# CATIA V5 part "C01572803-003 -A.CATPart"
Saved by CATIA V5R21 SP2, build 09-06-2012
Part number: C01572803-003
Revision: ---
Description: PROPRIETARY NOTICE (do not delete / modify)  ***************************************************************************************************  LA SOCIETE EN COMMANDITE  AIRBUS CANADA  ("AIRBUS CANADA")  PAR  L'INTERMEDIAIRE  DE  SES  DIVISIONS  ET/OU  FILIALES  CORPORATIVES,  FOURNIT  LES PRESENTES  INFORMATIONS  AU  GOUVERNEMENT  A  TITRE CONFIDENTIEL. CES  INFORMATIONS ONT UNE TENEUR CONFIDENTIELLE,  AVEC DROITS DE PROPRIETE,  ET NOUS LES CONSIDERONS  EXCLUS  DE   L'APPLICATION  DE  LA LOI SUR L'ACCES A L'INFORMATION  (CANADA),  LES  LOIS  SUR  L'ACCES  A  L'INFORMATION  EUROPEENNES,  LE FREEDOM OF INFORMATION ACT (ETATS-UNIS) ET D'AUTRES LOIS SEMBLABLES. ELLES  PEUVENT  AUSSI  CONSTITUER DES SECRETS INDUSTRIELS DE NOTRE SOCIETE OU DE TIERCES PARTIES. LA DIVULGATION  PUBLIQUE  DE CES  INFORMATIONS NUIRAIT A AIRBUS CANADA OU A DES TIERCES PARTIES.  CES INFORMATIONS PEUVENT EGALEMENT CONTENIR  DES DONNEES QUI SONT CONTROLEE PAR DES LOIS DE CONTROLE DES EXPORTATIONS DU CANADA, L’EUROPE OU LES  ETATS-  UNIS. TOUTE EXPORTATION OU REEXPORTATION DE DONNEES CONTROLEES SANS AUTORISATION EST STRICTEMENT INTERDITE.  TOUTE INTENTION DE LES DIVULGUER EN TOUT OU EN PARTIE DEVRA ETRE SIGNIFIEE A L'AVANCE ET PAR ECRIT AU VICE-  PRESIDENT, SERVICES JURIDIQUES ET CONFORMITE ET SECRETAIRE CORPORATIF D'AIRBUS CANADA.    AIRBUS CANADA LIMITED PARTNERSHIP  ("AIRBUS CANADA"),  BY ITS AFFILIATES AND/OR SUBSIDIARIES, PROVIDES THIS  INFORMATION TO THE GOVERNMENT IN CONFIDENCE. THIS IS PROPRIETARY CONFIDENTIAL INFORMATION WHICH WE CONSIDER  EXCLUDED  FROM  THE  APPLICATION OF THE ACCESS TO INFORMATION ACT (CANADA),  THE FREEDOM OF INFORMATION ACT  (U.S.A.),  THE ACCESS TO INFORMATION LAWS IN EUROPE, AND OTHER SIMILAR LEGISLATION. AND MAY ALSO CONSTITUTE  TRADE SECRETS OF OUR  COMPANY OR THIRD PARTIES.  PUBLIC  RELEASE  OF  THIS INFORMATION  WOULD BE HARMFUL TO  AIRBUS CANADA OR THIRD PARTIES.  THIS  INFORMATION  MAY  ALSO  CONTAIN DATA THAT IS CONTROLLED BY CANADIAN,  EUROPEAN, OR U.S.A. EXPORT CONTROL LAWS. ANY UNAUTHORIZED EXPORT OR RE-EXPORT OF ANY EXPORT CONTROLLED DATA  IS STRICTLY PROHIBITED  ANY INTENTION TO DISCLOSE SUCH INFORMATION,  OR  PART THEREOF,  MUST BE NOTIFIED IN  ADVANCE AND IN WRITING TO THE VICE PRESIDENT, LEGAL AND COMPLIANCE AND CORPORATE SECRETARY OF AIRBUS CANADA.        LES RENSEIGNEMENTS,  LES DONNEES  ET  DESSINS  TECHNIQUES  DIVULGUES  DANS  LES PRESENTES SONT LA PROPRIETE  EXCLUSIVE DE LA SOCIETE EN COMMANDITE AIRBUS CANADA ("AIRBUS CANADA") OU COMPORTENT DES DROITS DE PROPRIETE  APPARTENANT  A  AUTRUI ET NE PEUVENT ETRE DIVULGUES  A  QUICONQUE  NI  UTILISES PAR QUI QUE CE SOIT SANS LE  CONSENTEMENT  ECRIT  D’AIRBUS  CANADA.  LE DETENTEUR DES  PRESENTES  S'ENGAGE, DANS TOUTES CIRCONSTANCES, A  GARDER CONFIDENTIELS LES DONNEES ET DESSINS TECHNIQUES QU'ELLES CONTIENNENT.   CE QUI PRECEDE NE S'APPLIQUE  PAS  AUX PERSONNES  QUI  ONT DES DROITS DE PROPRIETE SUR CES RENSEIGNEMENTS,  DONNEES TECHNIQUES ET DESSINS  DANS LA MESURE OU CES DROITS EXISTENT.    THE INFORMATION,  TECHNICAL DATA  AND  DESIGNS DISCLOSED HEREIN ARE THE EXCLUSIVE PROPERTY OF AIRBUS CANADA  LIMITED PARTNERSHIP  ("AIRBUS CANADA")  OR  CONTAIN PROPRIETARY RIGHTS OF OTHERS  AND ARE NOT TO BE USED OR  DISCLOSED  TO  OTHERS WITHOUT THE WRITTEN CONSENT OF AIRBUS CANADA.  THE RECIPIENT OF THIS DOCUMENT, BY ITS  RETENTION  AND  USE  AGREES TO  HOLD  IN  CONFIDENCE  THE  TECHNICAL DATA AND DESIGNS CONTAINED HEREIN. THE  FOREGOING SHALL NOT APPLY TO PERSONS HAVING PROPRIETARY RIGHTS TO SUCH INFORMATION,  TECHNICAL DATA OR SUCH  DESIGNS TO THE EXTENT THAT SUCH RIGHTS EXIST.    Copyright 2020 Airbus Canada Limited Partnership. All Rights Reserved.  ***********************************
Property "Title": "SPACER, ROLLER SHAFT, SLIDE, OWE"
Property "Dataset Type": "DETAIL"
Property "Supplier Name And CAGE Code": "AIRBUS CANADA LIMITED PARTNERSHIP L0J48"
Property "Major Supplier Code": "LP"
Property "3D Only": "Y"
Property "Material Form": "BAR - ROUND"
Property "Finish Code": "S010"
Property "PCCN": "2"
Property "Organization": "DESIGN"
Property "Dimensions": "DIMENSIONS ARE IN INCHES"
Property "Roughness": "ALL MACHINED SURFACES 125 Ra MAX"
Property "Eng. Tolerances": "LINEAR .XX= +/-.03; .XXX= +/-.010; ANGULAR= +/-0.5 DEG"
Property "Tool Design Tolerances": "LINEAR .X= +/-.06; .XX= +/-.015; .XXX= +/-.005; .XXXX= +/-.001; ANGULAR= +/-0.5 DEG"
Property "Design Authority Program": "BD-500"
Property "Color Coded": "N"
Property "Thickness": 0
Property "Inside Diameter": 0
Property "Outside Diameter": 0.75
Property "Length": 0
Property "Width": 0
Property "Wall": 0
Property "Wire Gauge": "-"
Property "Alloy": "15-5PH"
Property "Final Condition": "H1025"
Property "Density": "N/A"
Property "Form": "N/A"
Property "Grade/Composition": "N/A"
Property "Material Class": "N/A"
Property "Mesh Cell Size": "-"
Property "Standard Spec Die": "-"
Property "Type": "N/A"
Property "Style": "N/A"
Property "MFG Process": "MACHINED"
Property "Material Specification Production": "AMS5659"
Property "Material Description Production": "CRES"
Property "Project": "BA"
Publications: "PartBody", "EXTRACT_DATUM_A", "EXTRACT_DATUM_B"
Material "ST-15-5PH-B": density 7833.41 kg/m3, Young's modulus 1.9719e+11 Pa, Poisson ratio 0.27
Bounding box of the stored display mesh (mm): x -6.342 to 6.342, y -11.43 to 4.572, z -6.342 to 6.342
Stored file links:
  C:\Users\CQQZ006\Desktop\A220钢钛件\舱门\C01572803-003\C01572803-003 -A.CATPart

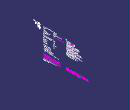
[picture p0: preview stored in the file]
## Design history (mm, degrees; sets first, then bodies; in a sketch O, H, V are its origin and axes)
AxisSystem1 "Absolute Axis System": origin (0, 0, 0), X (1, 0, 0), Y (0, 1, 0), Z (0, 0, 1)
Part_3D_Annotations1 "CATTPSSet"
Set1 "Geometrical Set for 3D Annotations"
  Set2 "No Show Geometry"
    Extract1 "EXTRACT_DATUM_A": ExtractElem face of Shaft1 from Sketch1.L2
    Extract2 "EXTRACT_DATUM_B": ExtractElem face of Shaft1 from Sketch1.L6
Body1 (main body)
  Sketch1 on yz-plane, origin (0, 0, 0), H (0, 1, 0), V (0, 0, 1)
    axis line L1 (-19.6215, 0) -> (29.3045, 0)
    point P1 (-19.6215, 0)
    line L2 (4.572, 2.0834) -> (-11.43, 2.0834)
    line L3 (-11.43, 2.0834) -> (-11.43, 3.1509)
    line L4 (-1.524, 3.5319) -> (-1.524, 6.35)
    line L5 (-1.524, 6.35) -> (0, 6.35)
    line L6 (0, 6.35) -> (0, 3.5471)
    line L7 (0.381, 3.1661) -> (4.064, 3.1661)
    line L8 (4.572, 2.8728) -> (4.572, 2.0834)
    line L9 (4.064, 3.1661) -> (4.572, 2.8728)
    point P4 (4.064, 3.1661)
    arc A1 centre (-1.905, 3.5319) radius 0.381 from (-1.524, 3.5319) to (-1.905, 3.1509) cw
    arc A2 centre (0.381, 3.5471) radius 0.381 from (0, 3.5471) to (0.381, 3.1661) ccw
    construction line L10 (-1.016, 6.35) -> (-1.524, 5.842)
    point P11 (-1.016, 6.35)
    line L11 (-11.43, 3.1509) -> (-1.905, 3.1509)
    point P16 (-1.524, 5.842)
    point P17 (-1.016, 6.35)
    distance L4 L6 = 1.524
    distance L8 L6 = 4.572
    distance L2 L1 = 2.0834
    distance L7 L1 = 3.1661
    distance L5 L1 = 6.35
    angle L7 L9 = 30
    distance P4 L8 = 0.508
    radius A1 = 0.381
    radius A2 = 0.381
    angle L5 L10 = 45
    distance L4 P11 = 0.508
    distance L6 L3 = 11.43
    distance L11 L1 = 3.1509
    coincidence: P1 H, L6 V, P11 L5, P11 L10, P16 L4, P17 L5
    horizontal: L1 H, L2 H, L5 H, L7 H, L11 H
    vertical: L3 V, L4 V, L6 V, L8 V
    tangency: A1 L4, A2 L6, A2 L7, A1 L11
  Shaft1: profile Sketch1, axis Sketch1.L1, angle 360
  Chamfer1: length 0.508, second length 0.508, on edge [face of Shaft1 from Sketch1.L4 | face of Shaft1 from Sketch1.L5]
